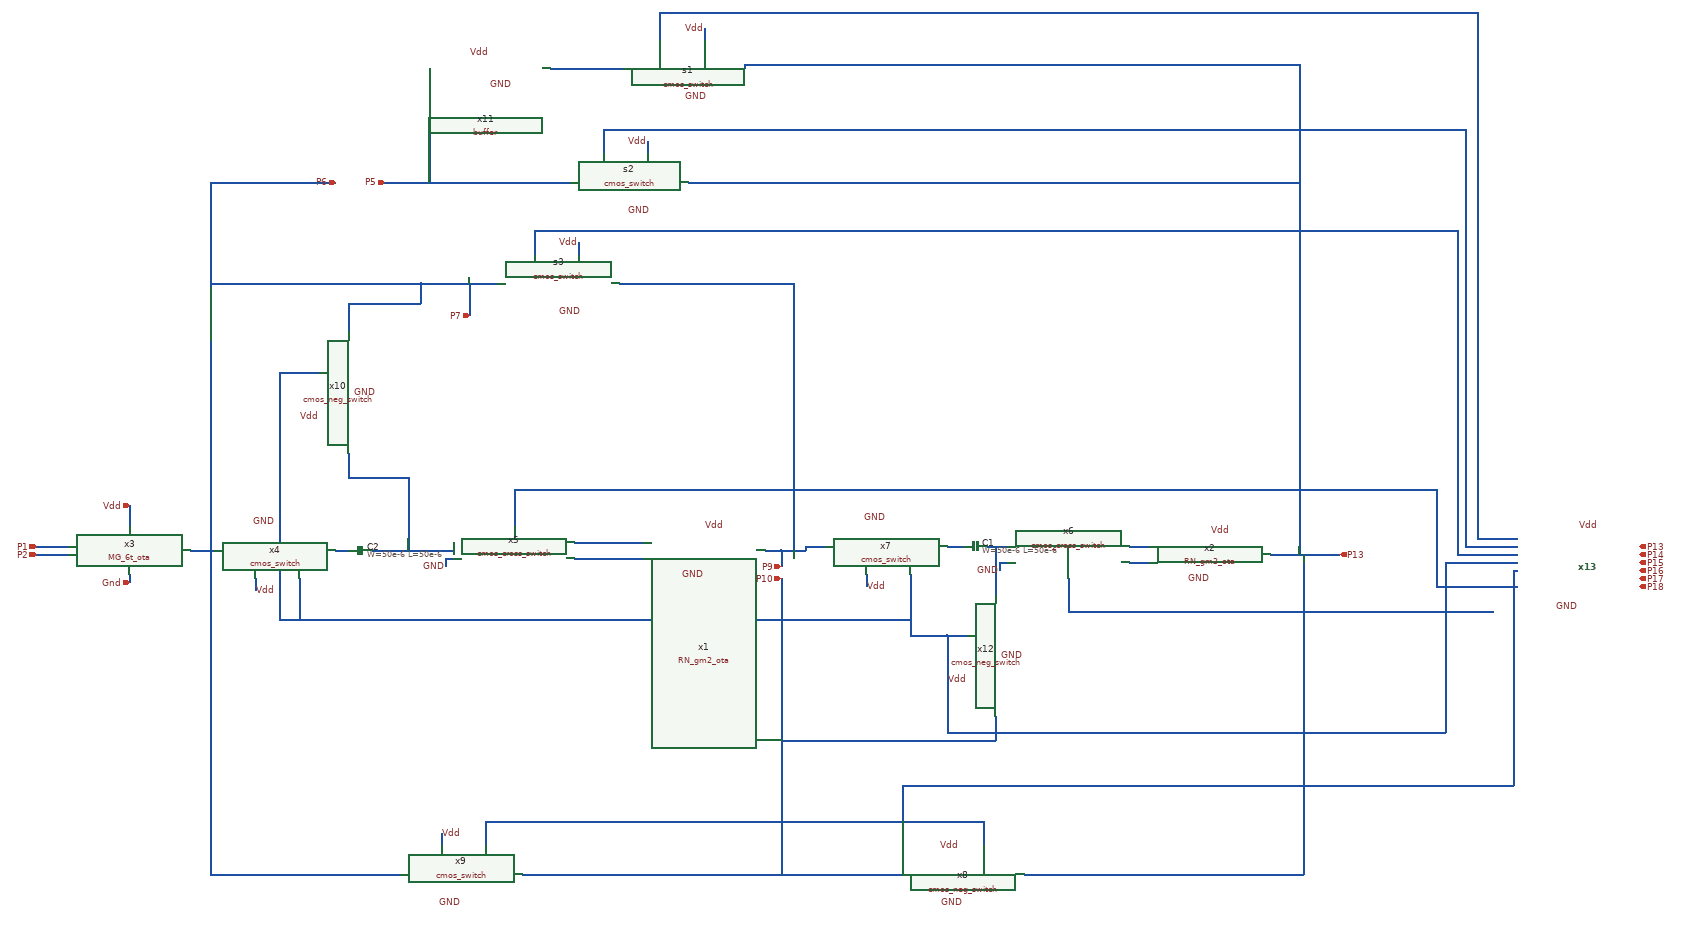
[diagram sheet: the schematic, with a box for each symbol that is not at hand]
v {xschem version=3.4.8RC file_version=1.3}
G {}
K {}
V {}
S {}
F {}
E {}
N 1000 -100 1040 -100 {lab=P9}
N -420 -100 -360 -100 {lab=P7}
N -570 -210 -570 -160 {lab=Vdd}
N -260 -30 -260 0 {lab=Vdd}
N -570 -40 -570 -20 {lab=Gnd}
N 530 -120 700 -120 {lab=#net1}
N 530 -80 700 -80 {lab=#net2}
N 210 -80 230 -80 {lab=GND}
N 210 -80 210 -60 {lab=GND}
N 60 -100 230 -100 {lab=#net3}
N 230 -120 230 -100 {lab=#net3}
N 1580 -70 1600 -70 {lab=GND}
N 1580 -70 1580 -50 {lab=GND}
N 1900 -110 1950 -110 {lab=#net4}
N 1900 -70 1950 -70 {lab=#net5}
N 1550 -110 1600 -110 {lab=#net6}
N 1250 -40 1250 -10 {lab=Vdd}
N 1450 -110 1490 -110 {lab=#net7}
N 1040 -100 1100 -100 {lab=P9}
N 1100 -110 1100 -100 {lab=P9}
N 1100 -110 1150 -110 {lab=P9}
N -800 -110 -730 -110 {lab=P1}
N -730 -110 -720 -110 {lab=P1}
N -800 -90 -720 -90 {lab=P2}
N -30 70 1350 70 {lab=#net8}
N 1350 70 1360 70 {lab=#net8}
N 1360 -40 1360 70 {lab=#net8}
N 1040 -100 1040 -60 {lab=P9}
N -30 -340 -30 -280 {lab=#net3}
N -30 -280 120 -280 {lab=#net3}
N 120 -280 120 -100 {lab=#net3}
N -30 -710 -30 -640 {lab=P7}
N -30 -710 150 -710 {lab=P7}
N 150 -760 150 -710 {lab=P7}
N 150 -760 340 -760 {lab=P7}
N 540 -860 540 -830 {lab=Vdd}
N 640 -760 1070 -760 {lab=P9}
N 1070 -760 1070 -100 {lab=P9}
N -330 -760 150 -760 {lab=P7}
N -370 -760 -330 -760 {lab=P7}
N 270 -760 270 -680 {lab=P7}
N -60 -100 -30 -100 {lab=#net9}
N 30 -100 60 -100 {lab=#net3}
N -370 -760 -370 -100 {lab=P7}
N -370 -100 -370 700 {lab=P7}
N -370 700 100 700 {lab=P7}
N 200 600 200 630 {lab=Vdd}
N 400 700 840 700 {lab=P10}
N 2250 -90 2420 -90 {lab=P13}
N 2330 -90 2330 700 {lab=P13}
N 840 700 1340 700 {lab=P10}
N 1640 700 2330 700 {lab=P13}
N 1040 -30 1040 700 {lab=P10}
N 710 -1110 710 -1080 {lab=Vdd}
N 810 -1010 2320 -1010 {lab=P13}
N 60 -1010 520 -1010 {lab=P5}
N -360 -1010 -60 -1010 {lab=P7}
N -370 -1010 -360 -1010 {lab=P7}
N -370 -1010 -370 -750 {lab=P7}
N 850 -1390 850 -1360 {lab=Vdd}
N 950 -1300 2320 -1300 {lab=P13}
N 470 -1290 650 -1290 {lab=#net10}
N 170 -1290 170 -1010 {lab=P5}
N 2320 -1300 2320 -90 {lab=P13}
N 1570 310 1570 370 {lab=P10}
N 1570 -110 1570 10 {lab=#net6}
N 1040 370 1560 370 {lab=P10}
N 1560 370 1570 370 {lab=P10}
N 310 570 310 630 {lab=#net11}
N 310 570 1540 570 {lab=#net11}
N 1540 570 1540 630 {lab=#net11}
N 740 -1430 740 -1360 {lab=#net12}
N 740 -1430 2760 -1430 {lab=#net12}
N 2760 -1430 2760 -130 {lab=#net12}
N 2760 -130 2860 -130 {lab=#net12}
N 600 -1140 600 -1090 {lab=#net13}
N 600 -1140 2730 -1140 {lab=#net13}
N 2730 -1140 2730 -120 {lab=#net13}
N 2730 -120 2730 -110 {lab=#net13}
N 2730 -110 2860 -110 {lab=#net13}
N 600 -1090 600 -1080 {lab=#net13}
N 950 -1300 950 -1290 {lab=P13}
N 430 -890 430 -840 {lab=#net14}
N 430 -890 2710 -890 {lab=#net14}
N 2710 -890 2710 -100 {lab=#net14}
N 2710 -100 2710 -90 {lab=#net14}
N 2710 -90 2860 -90 {lab=#net14}
N 430 -840 430 -830 {lab=#net14}
N 2680 -70 2860 -70 {lab=#net8}
N 2680 -70 2680 350 {lab=#net8}
N 1450 350 2680 350 {lab=#net8}
N 1450 110 1450 350 {lab=#net8}
N 1450 110 1500 110 {lab=#net8}
N 1750 -30 1750 50 {lab=#net15}
N 1750 50 2800 50 {lab=#net15}
N -150 70 -30 70 {lab=#net8}
N -150 -30 -150 70 {lab=#net8}
N -200 70 -150 70 {lab=#net8}
N -200 -540 -200 70 {lab=#net8}
N -200 -540 -100 -540 {lab=#net8}
N 1360 110 1450 110 {lab=#net8}
N 1360 70 1360 110 {lab=#net8}
N 1340 480 1340 570 {lab=#net11}
N 1340 480 2850 480 {lab=#net11}
N 2850 -50 2850 480 {lab=#net11}
N 2850 -50 2860 -50 {lab=#net11}
N 380 -250 380 -160 {lab=#net16}
N 380 -250 2660 -250 {lab=#net16}
N 2660 -250 2660 -10 {lab=#net16}
N 2660 -10 2860 -10 {lab=#net16}
C {RN_Gm2/RN_gm2_ota.sym} 850 -100 0 0 {name=x1}
C {RN_Gm3/RN_gm3_ota.sym} 2100 -90 0 0 {name=x2}
C {MG_6T_OTA/MG_6t_ota.sym} -570 -100 0 0 {name=x3}
C {symbols/cap_mim_2f0fF.sym} 0 -100 3 0 {name=C2
W=50e-6
L=50e-6
model=cap_mim_2f0fF
spiceprefix=X
m=30}
C {symbols/cap_mim_2f0fF.sym} 1520 -110 3 0 {name=C1
W=50e-6
L=50e-6
model=cap_mim_2f0fF
spiceprefix=X
m=30}
C {MG_switch/cmos_switch.sym} -210 -100 2 1 {name=x4}
C {lab_pin.sym} -260 0 2 0 {name=p24 sig_type=std_logic lab=Vdd}
C {lab_pin.sym} -210 -170 2 1 {name=p11 sig_type=std_logic lab=GND}
C {MG_switch/cmos_cross_switch.sym} 380 -100 0 0 {name=x5}
C {lab_pin.sym} 210 -60 0 0 {name=p1 sig_type=std_logic lab=GND}
C {MG_switch/cmos_cross_switch.sym} 1750 -90 2 1 {name=x6}
C {lab_pin.sym} 1580 -50 0 0 {name=p2 sig_type=std_logic lab=GND}
C {MG_switch/cmos_switch.sym} 1300 -110 2 1 {name=x7}
C {lab_pin.sym} 1250 -10 2 0 {name=p3 sig_type=std_logic lab=Vdd}
C {lab_pin.sym} 1300 -180 2 1 {name=p4 sig_type=std_logic lab=GND}
C {iopin.sym} -570 -210 0 0 {name=p12 lab=Vdd}
C {iopin.sym} -570 -20 0 0 {name=p5 lab=Gnd}
C {ipin.sym} -800 -110 0 0 {name=p6 lab=P1}
C {ipin.sym} -800 -90 0 0 {name=p7 lab=P2
}
C {iopin.sym} 1040 -60 0 0 {name=p8 lab=P9}
C {iopin.sym} 1040 -30 0 0 {name=p9 lab=P10}
C {lab_pin.sym} 850 -160 2 0 {name=p10 sig_type=std_logic lab=Vdd}
C {lab_pin.sym} 2100 -150 2 0 {name=p13 sig_type=std_logic lab=Vdd}
C {opin.sym} 2420 -90 0 0 {name=p14 lab=P13}
C {MG_switch/cmos_switch.sym} 490 -760 0 1 {name=s3}
C {lab_pin.sym} 540 -860 0 0 {name=p17 sig_type=std_logic lab=Vdd}
C {lab_pin.sym} 490 -690 0 1 {name=p18 sig_type=std_logic lab=GND}
C {iopin.sym} 270 -680 0 0 {name=p19 lab=P7}
C {MG_switch/cmos_switch.sym} 250 700 0 0 {name=x9}
C {lab_pin.sym} 200 600 0 1 {name=p20 sig_type=std_logic lab=Vdd}
C {lab_pin.sym} 250 770 0 0 {name=p21 sig_type=std_logic lab=GND}
C {MG_switch/cmos_neg_switch.sym} 1490 700 0 0 {name=x8}
C {MG_switch/cmos_neg_switch.sym} -30 -490 3 0 {name=x10}
C {lab_pin.sym} -100 -430 3 0 {name=p15 sig_type=std_logic lab=Vdd}
C {lab_pin.sym} 40 -490 1 1 {name=p16 sig_type=std_logic lab=GND}
C {MG_switch/cmos_switch.sym} 660 -1010 0 1 {name=s2}
C {lab_pin.sym} 710 -1110 0 0 {name=p22 sig_type=std_logic lab=Vdd}
C {lab_pin.sym} 660 -940 0 1 {name=p23 sig_type=std_logic lab=GND}
C {iopin.sym} 60 -1010 2 0 {name=p25 lab=P5}
C {iopin.sym} -60 -1010 0 0 {name=p26 lab=P6}
C {MG_switch/cmos_switch.sym} 800 -1290 0 1 {name=s1}
C {lab_pin.sym} 850 -1390 0 0 {name=p28 sig_type=std_logic lab=Vdd}
C {lab_pin.sym} 800 -1220 0 1 {name=p29 sig_type=std_logic lab=GND}
C {RN_buffer/buffer.sym} 320 -1290 0 1 {name=x11}
C {lab_pin.sym} 320 -1330 0 0 {name=p27 sig_type=std_logic lab=Vdd}
C {lab_pin.sym} 320 -1250 0 1 {name=p30 sig_type=std_logic lab=GND}
C {MG_switch/cmos_neg_switch.sym} 1570 160 3 0 {name=x12}
C {lab_pin.sym} 1500 220 3 0 {name=p31 sig_type=std_logic lab=Vdd}
C {lab_pin.sym} 1640 160 1 1 {name=p32 sig_type=std_logic lab=GND}
C {MG_decoder/MG_decoder.sym} 3010 -60 0 1 {name=x13}
C {lab_pin.sym} 3010 -160 2 0 {name=p33 sig_type=std_logic lab=Vdd}
C {lab_pin.sym} 1430 630 2 0 {name=p34 sig_type=std_logic lab=Vdd}
C {lab_pin.sym} 2100 -30 1 1 {name=p35 sig_type=std_logic lab=GND}
C {lab_pin.sym} 3010 40 1 1 {name=p36 sig_type=std_logic lab=GND}
C {ipin.sym} 3160 -110 0 1 {name=p37 lab=P13}
C {ipin.sym} 3160 -90 0 1 {name=p38 lab=P14}
C {ipin.sym} 3160 -70 0 1 {name=p39 lab=P15}
C {ipin.sym} 3160 -50 0 1 {name=p40 lab=P16}
C {ipin.sym} 3160 -30 0 1 {name=p41 lab=P17}
C {ipin.sym} 3160 -10 0 1 {name=p42 lab=P18}
C {lab_pin.sym} 1490 770 0 0 {name=p43 sig_type=std_logic lab=GND}
C {lab_pin.sym} 850 -40 2 1 {name=p44 sig_type=std_logic lab=GND}
